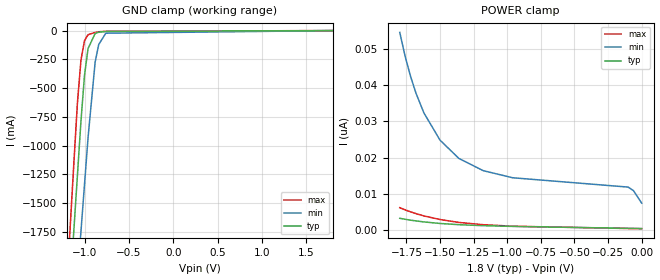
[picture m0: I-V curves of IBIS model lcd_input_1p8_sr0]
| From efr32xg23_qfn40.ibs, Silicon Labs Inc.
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|   Model lcd_input_1p8_sr0
[Model]  lcd_input_1p8_sr0
Model_type Input
C_comp   1.6300pF   1.4000pF   2.7000pF
[Temperature Range]   25.0000   0.1250k   -40.0000
[Pullup Reference]   1.8000V   1.6200V   1.9800V
[Pulldown Reference]   0.0V   0.0V   0.0V
[POWER Clamp Reference]   1.8000V   1.6200V   1.9800V
[GND Clamp Reference]   0.0V   0.0V   0.0V
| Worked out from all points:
|   GND clamp passes 1 mA (typ) near -0.56 V on its own axis
[GND_clamp]
|Voltage   I(typ)   I(min)   I(max)
-1.8V     -9.867A    -9.569A    -10.32A
-1.2V     -2.688A    -3.389A    -2.223A
-1.16V    -2.211A    -2.978A    -1.687A
-1.12V    -1.735A    -2.567A    -1.152A
-1.08V    -1.26A     -2.157A    -630.3mA
-1.04V    -786.2mA   -1.747A    -256.2mA
-1V       -388.1mA   -1.338A    -87.58mA
-960mV    -155.8mA   -930mA     -35.74mA
-880mV    -25.03mA   -272.7mA   -16.29mA
-840mV    -13.92mA   -121.5mA   -10.46mA
-760mV    -7.819mA   -22.78mA   -6.532mA
1.8V      420.7pA    11.94nA    334.2pA
[POWER_clamp]
|Voltage   I(typ)   I(min)   I(max)
-1.8V     3.264nA    54.56nA    6.193nA
-1.76V    2.994nA    47.98nA    5.591nA
-1.72V    2.754nA    42.48nA    5.047nA
-1.68V    2.541nA    37.87nA    4.559nA
-1.62V    2.263nA    32.33nA    3.919nA
-1.5V     1.838nA    24.81nA    2.92nA
-1.36V    1.501nA    19.78nA    2.122nA
-1.18V    1.228nA    16.42nA    1.492nA
-960mV    1.024nA    14.45nA    1.077nA
-100mV    499.2pA    11.87nA    445.7pA
-60mV     472.6pA    10.86nA    433.4pA
0V        420.7pA    7.448nA    403.8pA
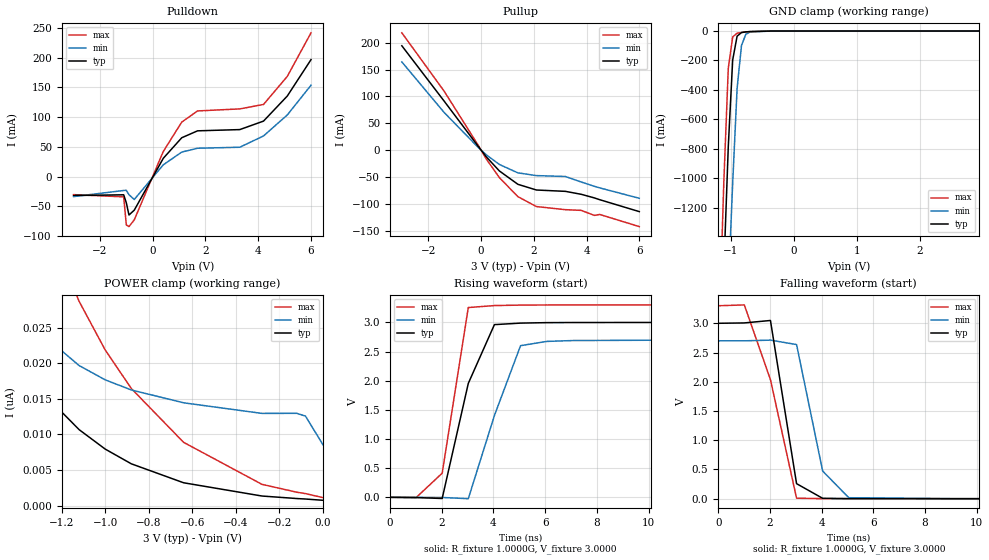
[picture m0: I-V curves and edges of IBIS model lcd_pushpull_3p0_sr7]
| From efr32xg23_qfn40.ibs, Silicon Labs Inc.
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|   Model lcd_pushpull_3p0_sr7
[Model]  lcd_pushpull_3p0_sr7
Model_type 3-state
Polarity   Non-Inverting
Enable   Active-High
C_comp   1.6300pF   1.4000pF   2.7000pF
[Temperature Range]   25.0000   0.1250k   -40.0000
[Pullup Reference]   3.0000V   2.7000V   3.3000V
[Pulldown Reference]   0.0V   0.0V   0.0V
[POWER Clamp Reference]   3.0000V   2.7000V   3.3000V
[GND Clamp Reference]   0.0V   0.0V   0.0V
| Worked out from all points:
|   slope of the pulldown table from 0 to 0.45 V, typ, clamps not added: 13.2 ohm
|   slope of the pullup table from 0 to 0.45 V, typ, clamps not added: 16.9 ohm
|   GND clamp passes 1 mA (typ) near -0.56 V on its own axis
|   rising waveform, R_fixture 1.0000G, V_fixture 3.0000: 20-80 % time 1.14ns typ, 1.25ns min, 704ps max; typ from 0 V to 3 V
|   falling waveform, R_fixture 1.0000G, V_fixture 3.0000: 20-80 % time 651ps typ, 756ps min, 1.16ns max; typ from 3 V to 0 V
[Pulldown]
|Voltage   I(typ)   I(min)   I(max)
-3V       -31.58mA   -33.4mA    -30.1mA
-1.1V     -30.4mA    -23.12mA   -33.84mA
-1V       -43.97mA   -22.88mA   -81.12mA
-900mV    -64.37mA   -30.22mA   -83.83mA
-700mV    -56.23mA   -38.35mA   -72.61mA
400mV     30.95mA    19.99mA    42.35mA
1.1V      65.5mA     41.43mA    91.79mA
1.7V      77.14mA    47.89mA    110.6mA
3.3V      79.23mA    49.55mA    114mA
4.2V      93.5mA     68.54mA    121.5mA
5.1V      135.6mA    103.8mA    168.6mA
6V        196.8mA    153.8mA    241.9mA
[Pullup]
|Voltage   I(typ)   I(min)   I(max)
-3V       194.2mA    164.1mA    218.3mA
-1.4V     91.4mA     70.21mA    109.9mA
-100mV    6.625mA    4.686mA    8.557mA
200mV     -12.59mA   -8.838mA   -16.56mA
700mV     -39mA      -26.89mA   -51.48mA
1.4V      -63.77mA   -42.47mA   -86.76mA
2.1V      -74.37mA   -47.55mA   -105.2mA
3.2V      -76.89mA   -49.24mA   -111mA
3.8V      -82.38mA   -59.49mA   -112.3mA
4.3V      -89.13mA   -67.54mA   -121.7mA
4.5V      -92.42mA   -70.43mA   -119.9mA
6V        -114.6mA   -89.81mA   -142.5mA
[GND_clamp]
|Voltage   I(typ)   I(min)   I(max)
-3V       -24.27A    -21.95A    -26.57A
-1.18V    -2.447A    -3.183A    -1.952A
-1.11V    -1.614A    -2.464A    -1.015A
-1.04V    -784mA     -1.746A    -252.8mA
-970mV    -196.2mA   -1.031A    -40.03mA
-900mV    -35mA      -390.7mA   -14.95mA
-830mV    -10.34mA   -96.94mA   -9.948mA
-760mV    -5.711mA   -21.43mA   -6.561mA
-690mV    -3.47mA    -6.05mA    -3.879mA
-340mV    -10.36uA   -45.49uA   -3.3uA
2.95V     657.9pA    12.89nA    538.5pA
[POWER_clamp]
|Voltage   I(typ)   I(min)   I(max)
-3V       338.2nA    9.289uA    586.7nA
-1.56V    29.18nA    39.44nA    70.52nA
-1.4V     20.57nA    28.74nA    51.74nA
-1.28V    15.63nA    23.83nA    40.5nA
-1.12V    10.68nA    19.68nA    28.7nA
-1V       7.945nA    17.67nA    21.86nA
-880mV    5.879nA    16.25nA    16.45nA
-640mV    3.219nA    14.45nA    8.897nA
-280mV    1.357nA    12.96nA    2.997nA
-120mV    1.003nA    12.97nA    1.894nA
-80mV     936.4pA    12.58nA    1.698nA
0V        757.3pA    8.576nA    1.134nA
[Ramp]
| variable   typ   min   max
dV/dt_r  1.7971/1.1476n   1.6163/1.2582n   1.9775/0.7045n
dV/dt_f  1.7980/0.6538n   1.6172/0.7624n   1.9783/1.1625n
R_load = 10.0000k
[Rising Waveform]
R_fixture= 1.0000G
V_fixture= 3.0000
V_fixture_min= 2.7000
V_fixture_max= 3.3000
|time   V(typ)   V(min)   V(max)
0s        2.714uV    4.972uV    1.54uV
1.01ns    -4.146mV   -950.5uV   -5.115mV
2.02ns    -20.05mV   -2.606mV   413.9mV
3.03ns    1.954V     -23.67mV   3.255V
4.04ns    2.962V     1.403V     3.289V
5.051ns   2.988V     2.601V     3.297V
6.061ns   2.996V     2.674V     3.299V
7.071ns   2.998V     2.689V     3.3V
13.13ns   3V         2.7V       3.3V
100ns     3V         2.7V       3.3V
[Falling Waveform]
R_fixture= 1.0000G
V_fixture= 3.0000
V_fixture_min= 2.7000
V_fixture_max= 3.3000
|time   V(typ)   V(min)   V(max)
0s        3V         2.7V       3.3V
1.01ns    3.006V     2.7V       3.314V
2.02ns    3.048V     2.712V     2.036V
3.03ns    257.3mV    2.636V     8.468mV
4.04ns    6.292mV    472.4mV    1.168mV
5.051ns   1.448mV    16.61mV    289.8uV
9.091ns   66.73uV    434.1uV    24.35uV
100ns     2.693uV    6.052uV    1.56uV
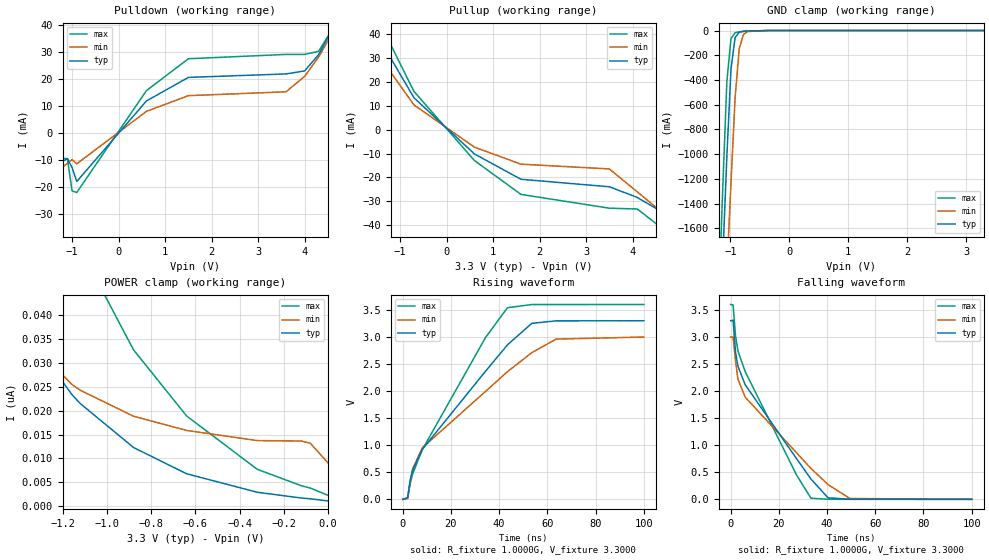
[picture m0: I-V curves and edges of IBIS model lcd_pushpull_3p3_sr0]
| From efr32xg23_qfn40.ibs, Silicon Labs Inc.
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|   Model lcd_pushpull_3p3_sr0
[Model]  lcd_pushpull_3p3_sr0
Model_type 3-state
Polarity   Non-Inverting
Enable   Active-High
C_comp   1.6300pF   1.4000pF   2.7000pF
[Temperature Range]   25.0000   0.1250k   -40.0000
[Pullup Reference]   3.3000V   3.0000V   3.6000V
[Pulldown Reference]   0.0V   0.0V   0.0V
[POWER Clamp Reference]   3.3000V   3.0000V   3.6000V
[GND Clamp Reference]   0.0V   0.0V   0.0V
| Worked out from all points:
|   slope of the pulldown table from 0 to 0.495 V, typ, clamps not added: 48.7 ohm
|   slope of the pullup table from 0 to 0.495 V, typ, clamps not added: 57.6 ohm
|   GND clamp passes 1 mA (typ) near -0.56 V on its own axis
|   rising waveform, R_fixture 1.0000G, V_fixture 3.3000: 20-80 % time 34.1ns typ, 40.2ns min, 26.8ns max; typ from 0 V to 3.3 V
|   falling waveform, R_fixture 1.0000G, V_fixture 3.3000: 20-80 % time 26.4ns typ, 30.2ns min, 21.8ns max; typ from 3.3 V to 0 V
[Pulldown]
|Voltage   I(typ)   I(min)   I(max)
-3.3V     -32.48mA   -36.78mA   -26.72mA
-1.2V     -10.41mA   -12.59mA   -9.355mA
-1.1V     -9.492mA   -11.16mA   -9.469mA
-1V       -12.79mA   -9.82mA    -21.42mA
-900mV    -17.92mA   -11.39mA   -21.97mA
600mV     11.83mA    7.984mA    15.65mA
1.5V      20.51mA    13.77mA    27.39mA
3.6V      21.79mA    15.2mA     28.99mA
4V        22.91mA    20.9mA     29mA
4.3V      28.91mA    28.04mA    30.13mA
4.7V      41.74mA    40.01mA    41.16mA
6.6V      135.1mA    124.4mA    142.2mA
[Pullup]
|Voltage   I(typ)   I(min)   I(max)
-3.3V     128.6mA    110.9mA    144.8mA
-1.9V     57.64mA    47.01mA    67.7mA
-1.7V     48.63mA    39.45mA    57.37mA
-1.5V     40.07mA    32.37mA    47.44mA
-700mV    13.41mA    10.43mA    16.1mA
600mV     -10.16mA   -7.306mA   -12.92mA
1.6V      -20.79mA   -14.45mA   -27.14mA
3.5V      -23.94mA   -16.45mA   -32.93mA
4.1V      -28.41mA   -26.06mA   -33.27mA
4.6V      -34.14mA   -34.13mA   -40.85mA
5.6V      -47.68mA   -46.64mA   -48.47mA
6.6V      -57.76mA   -56.29mA   -58.41mA
[GND_clamp]
|Voltage   I(typ)   I(min)   I(max)
-3.3V     -27.87A    -25.05A    -30.64A
-1.2V     -2.686A    -3.389A    -2.22A
-1.13V    -1.852A    -2.669A    -1.282A
-1.06V    -1.021A    -1.951A    -413.8mA
-990mV    -311.8mA   -1.235A    -64.72mA
-920mV    -56.25mA   -542.5mA   -17.8mA
-850mV    -13.45mA   -148.5mA   -11.08mA
-780mV    -6.591mA   -32.68mA   -7.457mA
-710mV    -4.029mA   -8.323mA   -4.574mA
-360mV    -18.91uA   -70.05uA   -6.844uA
3.3V      1.07nA     13.64nA    781.9pA
[POWER_clamp]
|Voltage   I(typ)   I(min)   I(max)
-3.28V    727.8nA    32.99uA    1.086uA
-1.6V     57.64nA    55.61nA    128.6nA
-1.56V    53.42nA    50.92nA    120.3nA
-1.4V     38.98nA    37.13nA    91.2nA
-1.16V    23.46nA    25.56nA    58.31nA
-1.12V    21.47nA    24.28nA    53.91nA
-880mV    12.29nA    18.85nA    32.79nA
-640mV    6.783nA    15.87nA    18.92nA
-320mV    2.894nA    13.73nA    7.713nA
-120mV    1.684nA    13.64nA    4.257nA
-80mV     1.52nA     13.19nA    3.779nA
0V        1.07nA     9.091nA    2.25nA
[Ramp]
| variable   typ   min   max
dV/dt_r  1.9617/37.0242n   1.7688/45.3295n   2.1477/28.3047n
dV/dt_f  1.9693/29.4329n   1.7815/35.6043n   2.1526/23.4418n
R_load = 10.0000k
[Rising Waveform]
R_fixture= 1.0000G
V_fixture= 3.3000
V_fixture_min= 3.0000
V_fixture_max= 3.6000
|time   V(typ)   V(min)   V(max)
0s        212.3uV    401.5uV    127.4uV
2.02ns    29.92mV    25.4mV     16.45mV
3.03ns    337.6mV    310.8mV    279.7mV
4.04ns    529.4mV    558.1mV    461.4mV
8.081ns   920.7mV    951.4mV    915mV
34.34ns   2.367V     1.994V     2.989V
43.43ns   2.853V     2.358V     3.54V
53.54ns   3.252V     2.71V      3.599V
63.64ns   3.298V     2.961V     3.599V
100ns     3.3V       2.999V     3.6V
[Falling Waveform]
R_fixture= 1.0000G
V_fixture= 3.3000
V_fixture_min= 3.0000
V_fixture_max= 3.6000
|time   V(typ)   V(min)   V(max)
0s        3.3V       2.999V     3.6V
1.01ns    3.31V      2.997V     3.591V
2.02ns    2.719V     2.559V     3.02V
3.03ns    2.457V     2.218V     2.739V
6.061ns   2.115V     1.887V     2.358V
27.27ns   755.7mV    863.5mV    454.2mV
33.33ns   374.4mV    570.6mV    20.5mV
40.4ns    28mV       272.1mV    959.5uV
49.49ns   1.325mV    15.29mV    469.3uV
100ns     214.5uV    417uV      127.9uV
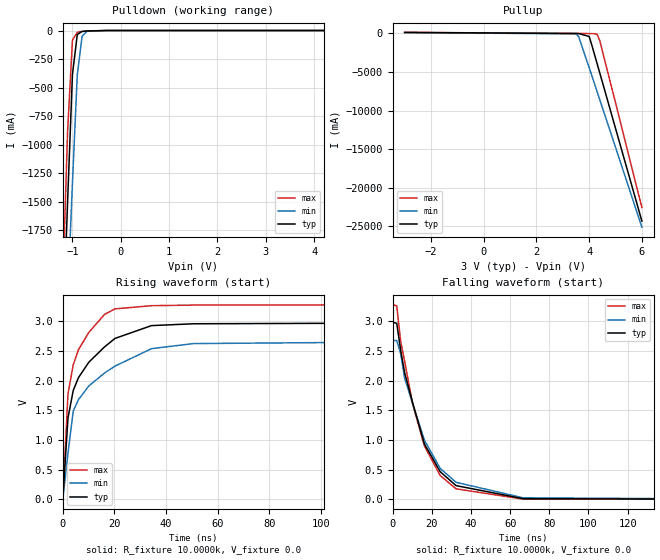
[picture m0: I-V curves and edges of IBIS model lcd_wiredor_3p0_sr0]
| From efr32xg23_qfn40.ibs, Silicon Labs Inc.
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|   Model lcd_wiredor_3p0_sr0
[Model]  lcd_wiredor_3p0_sr0
Model_type Output
Polarity   Non-Inverting
Enable   Active-Low
C_comp   1.6300pF   1.4000pF   2.7000pF
[Temperature Range]   25.0000   0.1250k   -40.0000
[Pullup Reference]   3.0000V   2.7000V   3.3000V
[Pulldown Reference]   0.0V   0.0V   0.0V
[POWER Clamp Reference]   3.0000V   2.7000V   3.3000V
[GND Clamp Reference]   0.0V   0.0V   0.0V
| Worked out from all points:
|   slope of the pullup table from 0 to 0.45 V, typ, clamps not added: 61.2 ohm
|   rising waveform, R_fixture 10.0000k, V_fixture 0.0: 20-80 % time 10.8ns typ, 15.2ns min, 6.61ns max; typ from 0 V to 2.98 V
|   falling waveform, R_fixture 10.0000k, V_fixture 0.0: 20-80 % time 16.7ns typ, 18.3ns min, 15.1ns max; typ from 2.98 V to 0 V
[Pulldown]
|Voltage   I(typ)   I(min)   I(max)
-3V       -24.27A    -21.95A    -26.57A
-1.2V     -2.686A    -3.389A    -2.22A
-1.1V     -1.495A    -2.361A    -881.8mA
-1V       -385.8mA   -1.337A    -84.19mA
-900mV    -34.99mA   -390.7mA   -14.95mA
-800mV    -7.703mA   -50.4mA    -8.403mA
-700mV    -3.742mA   -7.062mA   -4.219mA
-300mV    -2.847uA   -17.98uA   -692.6nA
6V        338.2nA    35.99uA    408.8nA
[Pullup]
|Voltage   I(typ)   I(min)   I(max)
-3V       110.5mA    92.38mA    126.9mA
3.5V      -20.93mA   -70.49mA   -28.69mA
3.6V      -22.98mA   -412.2mA   -28.7mA
4V        -413.4mA   -4.443A    -35.96mA
4.1V      -1.522A    -5.474A    -42.03mA
4.2V      -2.714A    -6.505A    -50.3mA
4.3V      -3.912A    -7.537A    -120.8mA
4.4V      -5.109A    -8.569A    -915.3mA
4.5V      -6.307A    -9.602A    -2.255A
4.7V      -8.705A    -11.67A    -4.954A
4.8V      -9.905A    -12.7A     -6.304A
6V        -24.32A    -25.1A     -22.56A
[Ramp]
| variable   typ   min   max
dV/dt_r  1.7893/10.7796n   1.6058/15.1523n   1.9711/6.6087n
dV/dt_f  49.0481u/0.2795n   58.2800u/3.7685p   62.0810u/1.8445p
R_load = 10.0000k
[Rising Waveform]
R_fixture= 10.0000k
V_fixture= 0.0
V_fixture_min= 0.0
V_fixture_max= 0.0
|time   V(typ)   V(min)   V(max)
0s        4.624uV    47.91uV    4.748uV
2.02ns    1.373V     775.7mV    1.78V
4.04ns    1.834V     1.488V     2.267V
6.061ns   2.051V     1.681V     2.523V
10.1ns    2.313V     1.912V     2.816V
16.16ns   2.57V      2.13V      3.118V
20.2ns    2.713V     2.246V     3.211V
34.34ns   2.929V     2.54V      3.265V
50.51ns   2.96V      2.626V     3.275V
200ns     2.982V     2.676V     3.285V
[Falling Waveform]
R_fixture= 10.0000k
V_fixture= 0.0
V_fixture_min= 0.0
V_fixture_max= 0.0
|time   V(typ)   V(min)   V(max)
0s        2.984V     2.679V     3.286V
2.02ns    2.97V      2.679V     3.263V
4.04ns    2.511V     2.457V     2.66V
6.061ns   2.135V     2.042V     2.329V
10.1ns    1.634V     1.618V     1.613V
16.16ns   933.7mV    998.1mV    898.7mV
24.24ns   464.9mV    520.4mV    400.8mV
32.32ns   230.9mV    286.6mV    176.8mV
66.67ns   10mV       24.73mV    2.331mV
200ns     -452.1uV   290.5uV    -558.3uV
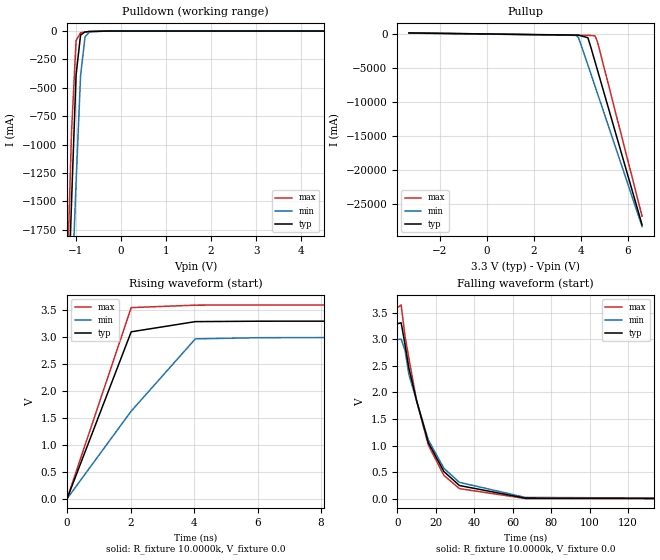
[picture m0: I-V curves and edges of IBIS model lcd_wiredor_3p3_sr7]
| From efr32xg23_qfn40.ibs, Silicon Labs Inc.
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|   Model lcd_wiredor_3p3_sr7
[Model]  lcd_wiredor_3p3_sr7
Model_type Output
Polarity   Non-Inverting
Enable   Active-Low
C_comp   1.6300pF   1.4000pF   2.7000pF
[Temperature Range]   25.0000   0.1250k   -40.0000
[Pullup Reference]   3.3000V   3.0000V   3.6000V
[Pulldown Reference]   0.0V   0.0V   0.0V
[POWER Clamp Reference]   3.3000V   3.0000V   3.6000V
[GND Clamp Reference]   0.0V   0.0V   0.0V
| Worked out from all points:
|   slope of the pullup table from 0 to 0.495 V, typ, clamps not added: 15.9 ohm
|   rising waveform, R_fixture 10.0000k, V_fixture 0.0: 20-80 % time 1.29ns typ, 2.44ns min, 1.23ns max; typ from 0 V to 3.29 V
|   falling waveform, R_fixture 10.0000k, V_fixture 0.0: 20-80 % time 16.2ns typ, 17.9ns min, 14.6ns max; typ from 3.29 V to 0 V
[Pulldown]
|Voltage   I(typ)   I(min)   I(max)
-3.3V     -27.87A    -25.05A    -30.64A
-1.2V     -2.686A    -3.389A    -2.22A
-1.1V     -1.495A    -2.361A    -881.8mA
-1V       -385.8mA   -1.337A    -84.19mA
-900mV    -35mA      -390.8mA   -14.95mA
-800mV    -7.709mA   -50.4mA    -8.405mA
-700mV    -3.744mA   -7.067mA   -4.22mA
-300mV    -2.853uA   -17.99uA   -699.1nA
6.6V      752.9nA    140.4uA    817.4nA
[Pullup]
|Voltage   I(typ)   I(min)   I(max)
-3.3V     221.2mA    195.6mA    241.7mA
3.8V      -92.93mA   -118.6mA   -128.7mA
3.9V      -95.18mA   -460.7mA   -128.9mA
4.3V      -487mA     -4.492A    -137mA
4.4V      -1.596A    -5.524A    -143.5mA
4.5V      -2.788A    -6.555A    -152.2mA
4.6V      -3.984A    -7.588A    -223.2mA
4.7V      -5.183A    -8.62A     -1.018A
4.8V      -6.381A    -9.652A    -2.357A
5V        -8.78A     -11.72A    -5.054A
5.1V      -9.98A     -12.75A    -6.408A
6.6V      -28.01A    -28.26A    -26.74A
[Ramp]
| variable   typ   min   max
dV/dt_r  1.9770/1.2898n   1.7962/2.4360n   2.1574/1.2292n
dV/dt_f  0.1325m/4.5745p   76.2395u/4.8026p   0.2279m/6.0981p
R_load = 10.0000k
[Rising Waveform]
R_fixture= 10.0000k
V_fixture= 0.0
V_fixture_min= 0.0
V_fixture_max= 0.0
|time   V(typ)   V(min)   V(max)
0s        5.069uV    44.89uV    5.493uV
2.02ns    3.097V     1.625V     3.546V
4.04ns    3.286V     2.966V     3.592V
6.061ns   3.294V     2.988V     3.595V
12.12ns   3.295V     2.994V     3.596V
200ns     3.295V     2.994V     3.596V
[Falling Waveform]
R_fixture= 10.0000k
V_fixture= 0.0
V_fixture_min= 0.0
V_fixture_max= 0.0
|time   V(typ)   V(min)   V(max)
0s        3.295V     2.994V     3.596V
2.02ns    3.312V     3.006V     3.649V
4.04ns    2.9V       2.792V     3.056V
6.061ns   2.454V     2.336V     2.64V
10.1ns    1.841V     1.834V     1.834V
16.16ns   1.054V     1.104V     1.008V
24.24ns   511.9mV    571.8mV    439.2mV
32.32ns   247.5mV    306.7mV    189.3mV
66.67ns   9.079mV    23.44mV    2.104mV
200ns     -487.8uV   160.8uV    -555.1uV
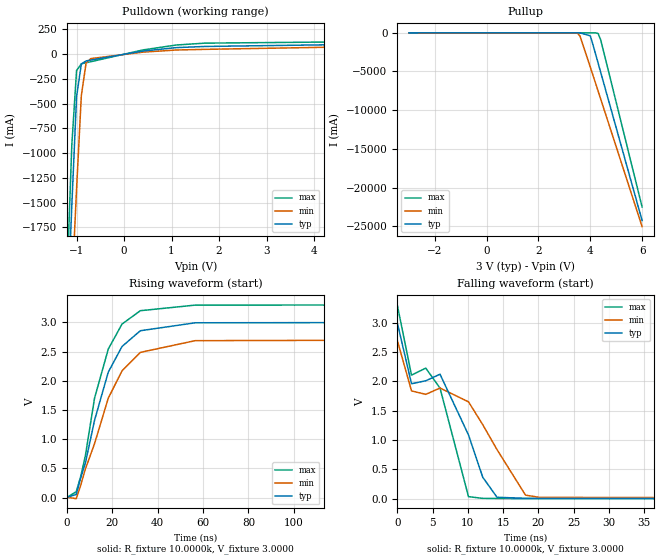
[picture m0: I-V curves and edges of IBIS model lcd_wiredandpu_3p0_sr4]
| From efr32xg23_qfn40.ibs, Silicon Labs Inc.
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|   Model lcd_wiredandpu_3p0_sr4
[Model]  lcd_wiredandpu_3p0_sr4
Model_type Output
Polarity   Inverting
Enable   Active-Low
C_comp   1.6300pF   1.4000pF   2.7000pF
[Temperature Range]   25.0000   0.1250k   -40.0000
[Pullup Reference]   3.0000V   2.7000V   3.3000V
[Pulldown Reference]   0.0V   0.0V   0.0V
[POWER Clamp Reference]   3.0000V   2.7000V   3.3000V
[GND Clamp Reference]   0.0V   0.0V   0.0V
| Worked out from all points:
|   slope of the pulldown table from 0 to 0.45 V, typ, clamps not added: 13.2 ohm
|   slope of the pullup table from 0 to 0.45 V, typ, clamps not added: 40.2 kohm
|   rising waveform, R_fixture 10.0000k, V_fixture 3.0000: 20-80 % time 13.1ns typ, 15.5ns min, 11.5ns max; typ from 0.003 V to 3 V
|   falling waveform, R_fixture 10.0000k, V_fixture 3.0000: 20-80 % time 10.3ns typ, 14.1ns min, 7.54ns max; typ from 3 V to 0.003 V
[Pulldown]
|Voltage   I(typ)   I(min)   I(max)
-3V       -24.3A     -21.99A    -26.6A
-1.2V     -2.716A    -3.412A    -2.254A
-1.1V     -1.526A    -2.385A    -915.6mA
-1V       -429.7mA   -1.36A     -165.3mA
-900mV    -99.37mA   -421mA     -98.78mA
-800mV    -69.26mA   -90.62mA   -87.32mA
-700mV    -59.97mA   -45.41mA   -76.82mA
400mV     30.95mA    19.99mA    42.35mA
1.1V      65.5mA     41.43mA    91.79mA
1.7V      77.14mA    47.89mA    110.6mA
4.2V      93.51mA    68.56mA    121.5mA
6V        196.9mA    153.8mA    241.9mA
[Pullup]
|Voltage   I(typ)   I(min)   I(max)
-3V       74.15uA    73.25uA    86.28uA
3.5V      -515.4uA   -50.46mA   -100.7uA
3.6V      -1.645mA   -390.8mA   -104.2uA
4V        -385.9mA   -4.417A    -4.327mA
4.1V      -1.495A    -5.447A    -8.512mA
4.2V      -2.686A    -6.476A    -15.06mA
4.3V      -3.882A    -7.507A    -84.3mA
4.4V      -5.077A    -8.538A    -881.9mA
4.5V      -6.274A    -9.569A    -2.22A
4.7V      -8.669A    -11.63A    -4.917A
4.8V      -9.868A    -12.66A    -6.266A
6V        -24.27A    -25.05A    -22.51A
[Ramp]
| variable   typ   min   max
dV/dt_r  0.3580/12.8648n   0.2880/14.3502n   0.4423/11.6048n
dV/dt_f  1.7980/10.2986n   1.6171/14.1264n   1.9783/7.5424n
R_load = 10.0000k
[Rising Waveform]
R_fixture= 10.0000k
V_fixture= 3.0000
V_fixture_min= 2.7000
V_fixture_max= 3.3000
|time   V(typ)   V(min)   V(max)
0s        3.394mV    4.689mV    2.757mV
4.04ns    53.19mV    -20.17mV   100.1mV
6.061ns   341.8mV    215.5mV    367.1mV
8.081ns   590.9mV    488.8mV    718.2mV
12.12ns   1.323V     923.2mV    1.703V
18.18ns   2.149V     1.702V     2.544V
24.24ns   2.588V     2.171V     2.972V
32.32ns   2.858V     2.487V     3.201V
56.57ns   2.994V     2.688V     3.297V
200ns     3V         2.7V       3.3V
[Falling Waveform]
R_fixture= 10.0000k
V_fixture= 3.0000
V_fixture_min= 2.7000
V_fixture_max= 3.3000
|time   V(typ)   V(min)   V(max)
0s        3V         2.7V       3.3V
2.02ns    1.959V     1.837V     2.105V
4.04ns    2.009V     1.778V     2.225V
6.061ns   2.121V     1.886V     1.885V
10.1ns    1.087V     1.651V     37.25mV
12.12ns   367.6mV    1.262V     8.566mV
14.14ns   27.15mV    838.5mV    6.037mV
18.18ns   8.527mV    63.5mV     4.632mV
20.2ns    7.097mV    24.75mV    4.344mV
200ns     3.395mV    4.693mV    2.758mV
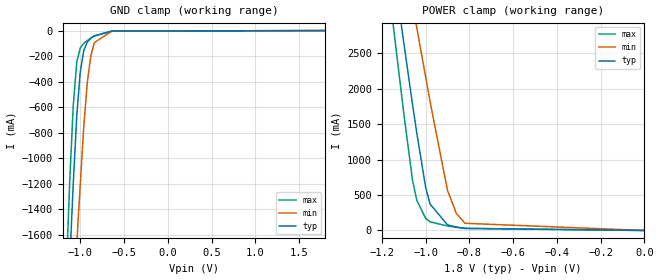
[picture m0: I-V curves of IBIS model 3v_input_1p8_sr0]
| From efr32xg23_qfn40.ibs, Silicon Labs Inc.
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|   Model 3v_input_1p8_sr0
[Model]  3v_input_1p8_sr0
Model_type Input
C_comp   1.6300pF   1.4000pF   2.7000pF
[Temperature Range]   25.0000   0.1250k   -40.0000
[Pullup Reference]   1.8000V   1.6200V   1.9800V
[Pulldown Reference]   0.0V   0.0V   0.0V
[POWER Clamp Reference]   1.8000V   1.6200V   1.9800V
[GND Clamp Reference]   0.0V   0.0V   0.0V
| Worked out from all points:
|   GND clamp passes 1 mA (typ) near -0.52 V on its own axis
|   POWER clamp passes 1 mA (typ) near -0.53 V on its own axis
[GND_clamp]
|Voltage   I(typ)   I(min)   I(max)
-1.8V     -14.24A    -14.11A    -14.46A
-1.16V    -2.476A    -3.328A    -1.893A
-1.12V    -1.809A    -2.723A    -1.176A
-1.08V    -1.199A    -2.174A    -584.5mA
-1.04V    -665.3mA   -1.671A    -246.2mA
-1V       -325.1mA   -1.206A    -136.4mA
-960mV    -156.4mA   -753.1mA   -99.65mA
-920mV    -90.21mA   -408.8mA   -78.05mA
-880mV    -60.4mA    -199.9mA   -59.73mA
-840mV    -41.37mA   -94.67mA   -43.12mA
-640mV    -3.804mA   -4.268mA   -4.1mA
1.8V      625.9pA    920.5nA    498.3pA
[POWER_clamp]
|Voltage   I(typ)   I(min)   I(max)
-1.8V     20.85A     19.71A     22.07A
-1.16V    4.023A     5.096A     3.217A
-1.14V    3.56A      4.702A     2.691A
-1.1V     2.657A     3.938A     1.662A
-1.06V    1.784A     3.203A     710.9mA
-1.04V    1.371A     2.858A     424.9mA
-1V       612.3mA    2.171A     172.3mA
-980mV    375.2mA    1.828A     122.5mA
-900mV    79.36mA    567.5mA    63.7mA
-860mV    47.61mA    243.6mA    45.04mA
-820mV    29.31mA    101.4mA    29.65mA
0V        625.9pA    9.472nA    580.1pA
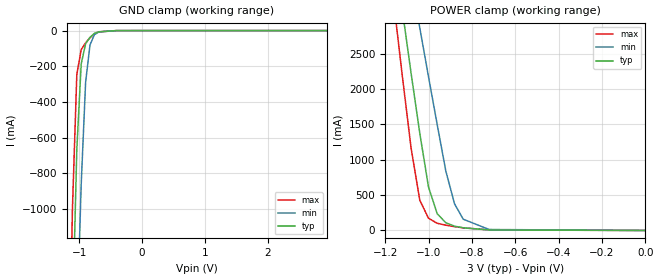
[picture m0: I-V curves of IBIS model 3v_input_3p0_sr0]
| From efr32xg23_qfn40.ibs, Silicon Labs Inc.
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|   Model 3v_input_3p0_sr0
[Model]  3v_input_3p0_sr0
Model_type Input
C_comp   1.6300pF   1.4000pF   2.7000pF
[Temperature Range]   25.0000   0.1250k   -40.0000
[Pullup Reference]   3.0000V   2.7000V   3.3000V
[Pulldown Reference]   0.0V   0.0V   0.0V
[POWER Clamp Reference]   3.0000V   2.7000V   3.3000V
[GND Clamp Reference]   0.0V   0.0V   0.0V
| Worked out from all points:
|   GND clamp passes 1 mA (typ) near -0.52 V on its own axis
|   POWER clamp passes 1 mA (typ) near -0.53 V on its own axis
[GND_clamp]
|Voltage   I(typ)   I(min)   I(max)
-3V       -32.58A    -30.59A    -34.3A
-1.18V    -2.82A     -3.643A    -2.261A
-1.11V    -1.644A    -2.575A    -1.001A
-1.04V    -666.4mA   -1.673A    -246.5mA
-970mV    -186.7mA   -861.8mA   -106.7mA
-900mV    -73.86mA   -290.7mA   -68.98mA
-830mV    -38.01mA   -80.48mA   -39.62mA
-760mV    -15.97mA   -23.02mA   -17.36mA
-690mV    -6.612mA   -7.853mA   -7.292mA
-410mV    -117.4uA   -298.1uA   -56.99uA
2.95V     978pA      6.282uA    846.4pA
[POWER_clamp]
|Voltage   I(typ)   I(min)   I(max)
-3V       48.87A     43.6A      53.88A
-1.16V    4.025A     5.101A     3.218A
-1.12V    3.102A     4.315A     2.168A
-1.08V    2.218A     3.569A     1.158A
-1.04V    1.372A     2.862A     425.9mA
-1V       614.1mA    2.175A     173.1mA
-960mV    237.5mA    1.499A     101.5mA
-920mV    109mA      838.4mA    74.91mA
-880mV    61.26mA    377.1mA    54.02mA
-840mV    37.84mA    159.1mA    37.05mA
-720mV    7.412mA    13.58mA    7.87mA
0V        1.019nA    10.64nA    1.026nA
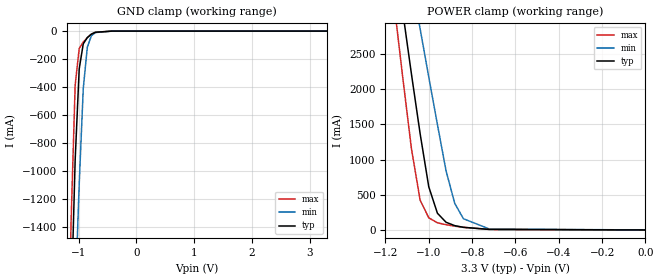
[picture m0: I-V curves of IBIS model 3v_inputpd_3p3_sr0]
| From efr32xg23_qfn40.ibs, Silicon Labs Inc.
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|   Model 3v_inputpd_3p3_sr0
[Model]  3v_inputpd_3p3_sr0
Model_type Input
C_comp   1.6300pF   1.4000pF   2.7000pF
[Temperature Range]   25.0000   0.1250k   -40.0000
[Pullup Reference]   3.3000V   3.0000V   3.6000V
[Pulldown Reference]   0.0V   0.0V   0.0V
[POWER Clamp Reference]   3.3000V   3.0000V   3.6000V
[GND Clamp Reference]   0.0V   0.0V   0.0V
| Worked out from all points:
|   GND clamp passes 1 mA (typ) near -0.52 V on its own axis
|   POWER clamp passes 1 mA (typ) near -0.52 V on its own axis
[GND_clamp]
|Voltage   I(typ)   I(min)   I(max)
-3.3V     -36.82A    -34.37A    -38.92A
-1.2V     -3.169A    -3.961A    -2.635A
-1.13V    -1.976A    -2.875A    -1.354A
-1.06V    -919.5mA   -1.925A    -386.3mA
-990mV    -269.8mA   -1.092A    -124.3mA
-920mV    -91.08mA   -411.1mA   -78.23mA
-850mV    -46.31mA   -116.2mA   -47.39mA
-780mV    -21.48mA   -33.47mA   -23.01mA
-710mV    -8.346mA   -10.37mA   -9.205mA
-430mV    -196.9uA   -429.1uA   -112.3uA
3.3V      74.76uA    87.41uA    86.61uA
[POWER_clamp]
|Voltage   I(typ)   I(min)   I(max)
-3.28V    55.25A     49.02A     61.14A
-1.16V    4.026A     5.102A     3.218A
-1.12V    3.102A     4.316A     2.168A
-1.08V    2.219A     3.57A      1.158A
-1.04V    1.373A     2.863A     426.1mA
-1V       614.5mA    2.175A     173.3mA
-960mV    237.8mA    1.5A       101.6mA
-920mV    109.3mA    839mA      75.07mA
-880mV    61.49mA    377.8mA    54.18mA
-840mV    38.03mA    159.6mA    37.2mA
-720mV    7.541mA    13.82mA    7.997mA
0V        74.76uA    59.13uA    94.48uA
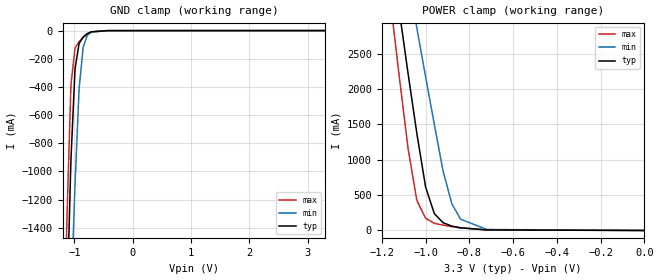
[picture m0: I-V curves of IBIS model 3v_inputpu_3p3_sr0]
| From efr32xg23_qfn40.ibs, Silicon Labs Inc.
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|   Model 3v_inputpu_3p3_sr0
[Model]  3v_inputpu_3p3_sr0
Model_type Input
C_comp   1.6300pF   1.4000pF   2.7000pF
[Temperature Range]   25.0000   0.1250k   -40.0000
[Pullup Reference]   3.3000V   3.0000V   3.6000V
[Pulldown Reference]   0.0V   0.0V   0.0V
[POWER Clamp Reference]   3.3000V   3.0000V   3.6000V
[GND Clamp Reference]   0.0V   0.0V   0.0V
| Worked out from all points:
|   GND clamp passes 1 mA (typ) near -0.51 V on its own axis
|   POWER clamp passes 1 mA (typ) near -0.53 V on its own axis
[GND_clamp]
|Voltage   I(typ)   I(min)   I(max)
-3.3V     -36.82A    -34.37A    -38.92A
-1.2V     -3.17A     -3.961A    -2.635A
-1.13V    -1.976A    -2.876A    -1.355A
-1.06V    -919.5mA   -1.925A    -386.4mA
-990mV    -269.9mA   -1.092A    -124.4mA
-920mV    -91.16mA   -411.2mA   -78.32mA
-850mV    -46.38mA   -116.3mA   -47.49mA
-780mV    -21.56mA   -33.53mA   -23.11mA
-710mV    -8.42mA    -10.43mA   -9.299mA
-430mV    -271.4uA   -488.1uA   -206.4uA
3.3V      1.119nA    28.31uA    -7.841uA
[POWER_clamp]
|Voltage   I(typ)   I(min)   I(max)
-3.28V    55.25A     49.02A     61.14A
-1.16V    4.026A     5.102A     3.218A
-1.12V    3.102A     4.316A     2.168A
-1.08V    2.218A     3.57A      1.158A
-1.04V    1.373A     2.863A     426mA
-1V       614.5mA    2.175A     173.2mA
-960mV    237.8mA    1.5A       101.5mA
-920mV    109.3mA    839mA      74.97mA
-880mV    61.41mA    377.7mA    54.08mA
-840mV    37.95mA    159.6mA    37.11mA
-720mV    7.466mA    13.76mA    7.903mA
0V        1.119nA    10.87nA    1.188nA
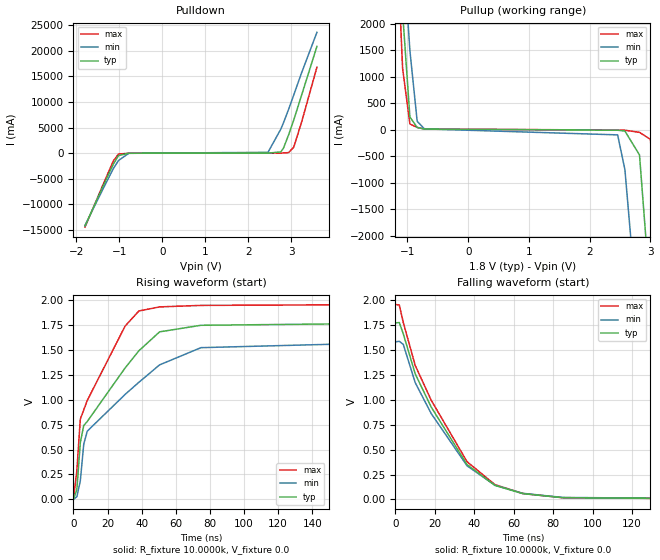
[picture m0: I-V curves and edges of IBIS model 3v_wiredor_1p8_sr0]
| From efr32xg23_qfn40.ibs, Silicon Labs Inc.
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|   Model 3v_wiredor_1p8_sr0
[Model]  3v_wiredor_1p8_sr0
Model_type Output
Polarity   Non-Inverting
Enable   Active-Low
C_comp   1.6300pF   1.4000pF   2.7000pF
[Temperature Range]   25.0000   0.1250k   -40.0000
[Pullup Reference]   1.8000V   1.6200V   1.9800V
[Pulldown Reference]   0.0V   0.0V   0.0V
[POWER Clamp Reference]   1.8000V   1.6200V   1.9800V
[GND Clamp Reference]   0.0V   0.0V   0.0V
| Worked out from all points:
|   slope of the pullup table from 0 to 0.27 V, typ, clamps not added: 170 ohm
|   rising waveform, R_fixture 10.0000k, V_fixture 0.0: 20-80 % time 31.7ns typ, 39.6ns min, 22.2ns max; typ from 0 V to 1.77 V
|   falling waveform, R_fixture 10.0000k, V_fixture 0.0: 20-80 % time 28.6ns typ, 29ns min, 29.1ns max; typ from 1.77 V to 0.001 V
[Pulldown]
|Voltage   I(typ)   I(min)   I(max)
-1.8V     -14.24A    -14.11A    -14.46A
-1.38V    -6.468A    -6.98A     -6.16A
-1.14V    -2.14A     -3.023A    -1.532A
-1.02V    -472.4mA   -1.439A    -175.3mA
-780mV    -21.13mA   -32.28mA   -22.88mA
2.46V     4.005mA    156.9mA    238.6uA
2.76V     235.8mA    4.702A     17.81mA
2.82V     958.6mA    5.911A     36.63mA
2.94V     3.56A      8.545A     100.8mA
3.06V     6.47A      11.36A     1.157A
3.24V     11.25A     15.63A     5.98A
3.6V      20.85A     23.6A      16.79A
[Pullup]
|Voltage   I(typ)   I(min)   I(max)
-1.8V     20.85A     19.71A     22.07A
-1.2V     4.979A     5.912A     4.301A
-1.08V    2.219A     3.567A     1.162A
-960mV    241.1mA    1.498A     109mA
-840mV    42.87mA    159.9mA    44.3mA
-720mV    12.28mA    16.09mA    14.65mA
2.46V     -8.699mA   -97.07mA   -6.739mA
2.58V     -25.15mA   -755.5mA   -8.985mA
2.82V     -476.4mA   -3.961A    -49.54mA
3V        -3.172A    -6.982A    -181.7mA
3.24V     -7.608A    -11.14A    -3.788A
3.6V      -14.25A    -16.86A    -11A
[Ramp]
| variable   typ   min   max
dV/dt_r  1.0634/31.6836n   0.9488/39.5880n   1.1753/22.2341n
dV/dt_f  2.4184u/14.3634n   53.2357u/30.9987n   4.5369u/2.3296p
R_load = 10.0000k
[Rising Waveform]
R_fixture= 10.0000k
V_fixture= 0.0
V_fixture_min= 0.0
V_fixture_max= 0.0
|time   V(typ)   V(min)   V(max)
0s        5.684uV    72.78uV    5.763uV
2.02ns    95.97mV    26.29mV    287.2mV
4.04ns    568.1mV    184.1mV    805.6mV
6.061ns   742mV      553.9mV    898.7mV
8.081ns   782.1mV    684.6mV    992.7mV
30.3ns    1.321V     1.055V     1.742V
38.38ns   1.494V     1.177V     1.894V
50.51ns   1.684V     1.352V     1.935V
74.75ns   1.75V      1.525V     1.95V
200ns     1.772V     1.581V     1.959V
[Falling Waveform]
R_fixture= 10.0000k
V_fixture= 0.0
V_fixture_min= 0.0
V_fixture_max= 0.0
|time   V(typ)   V(min)   V(max)
0s        1.773V     1.584V     1.959V
2.02ns    1.778V     1.589V     1.954V
4.04ns    1.664V     1.558V     1.778V
10.1ns    1.261V     1.173V     1.346V
18.18ns   928.7mV    863.5mV    997.5mV
36.36ns   349.7mV    337.7mV    378.9mV
50.51ns   140.8mV    142mV      148.5mV
64.65ns   57.81mV    61.04mV    59.18mV
84.85ns   17.38mV    19.7mV     16.91mV
200ns     956.4uV    1.285mV    776.6uV
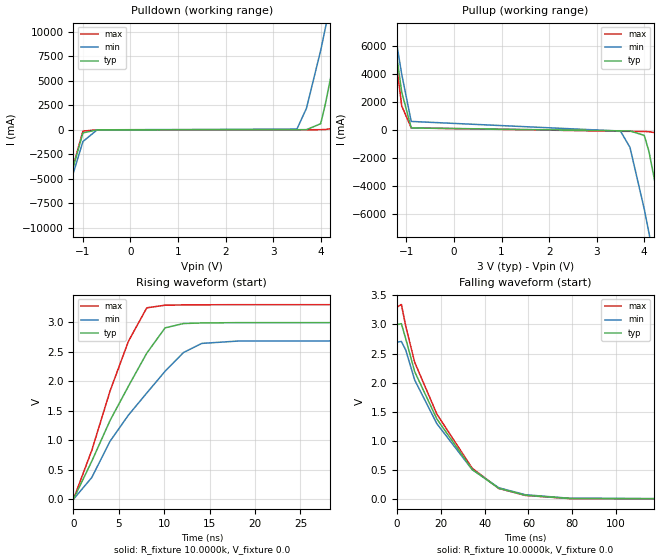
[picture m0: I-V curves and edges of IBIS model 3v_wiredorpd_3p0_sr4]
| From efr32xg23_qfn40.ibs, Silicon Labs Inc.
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|   Model 3v_wiredorpd_3p0_sr4
[Model]  3v_wiredorpd_3p0_sr4
Model_type Output
Polarity   Non-Inverting
Enable   Active-Low
C_comp   1.6300pF   1.4000pF   2.7000pF
[Temperature Range]   25.0000   0.1250k   -40.0000
[Pullup Reference]   3.0000V   2.7000V   3.3000V
[Pulldown Reference]   0.0V   0.0V   0.0V
[POWER Clamp Reference]   3.0000V   2.7000V   3.3000V
[GND Clamp Reference]   0.0V   0.0V   0.0V
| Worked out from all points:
|   slope of the pulldown table from 0 to 0.45 V, typ, clamps not added: 44.2 kohm
|   slope of the pullup table from 0 to 0.45 V, typ, clamps not added: 16.9 ohm
|   rising waveform, R_fixture 10.0000k, V_fixture 0.0: 20-80 % time 5.93ns typ, 7.46ns min, 4.36ns max; typ from 0 V to 3 V
|   falling waveform, R_fixture 10.0000k, V_fixture 0.0: 20-80 % time 26ns typ, 26.5ns min, 25.9ns max; typ from 3 V to 0.001 V
[Pulldown]
|Voltage   I(typ)   I(min)   I(max)
-3V       -32.58A    -30.59A    -34.3A
-1.6V     -10.63A    -10.8A     -10.59A
-1V       -326.2mA   -1.208A    -136.7mA
-700mV    -7.469mA   -9.021mA   -8.251mA
3.5V      668.1uA    66.94mA    91.83uA
3.7V      6.233mA    2.175A     116.2uA
4V        614.2mA    8.096A     6.599mA
4.1V      2.659A     10.42A     23.14mA
4.3V      7.504A     15.17A     173.2mA
4.4V      10.17A     17.48A     1.662A
4.7V      18.27A     24.04A     10.12A
6V        48.87A     49.4A      46.09A
[Pullup]
|Voltage   I(typ)   I(min)   I(max)
-3V       48.87A     43.6A      53.88A
-1.3V     7.53A      8.107A     7.175A
-1.1V     2.691A     3.958A     1.702A
-900mV    131.1mA    593mA      129.1mA
3.5V      -77.88mA   -95.53mA   -111.5mA
3.7V      -84.81mA   -1.257A    -111.9mA
4V        -403.8mA   -5.659A    -120.5mA
4.1V      -1.56A     -7.378A    -141.1mA
4.3V      -5.051A    -10.85A    -249.3mA
4.4V      -6.924A    -12.54A    -949.9mA
4.8V      -14.32A    -18.64A    -8.699A
6V        -32.66A    -34.42A    -29.76A
[Ramp]
| variable   typ   min   max
dV/dt_r  1.7973/5.9250n   1.6165/7.4590n   1.9777/4.3592n
dV/dt_f  0.3321/25.2938n   0.2660/26.8420n   0.4115/24.0269n
R_load = 10.0000k
[Rising Waveform]
R_fixture= 10.0000k
V_fixture= 0.0
V_fixture_min= 0.0
V_fixture_max= 0.0
|time   V(typ)   V(min)   V(max)
0s        8.184uV    73.48uV    10.86uV
2.02ns    643.8mV    368.1mV    826.5mV
4.04ns    1.335V     983.7mV    1.834V
6.061ns   1.914V     1.425V     2.674V
8.081ns   2.473V     1.799V     3.24V
10.1ns    2.901V     2.167V     3.284V
12.12ns   2.974V     2.483V     3.289V
14.14ns   2.984V     2.638V     3.291V
18.18ns   2.989V     2.678V     3.293V
200ns     2.995V     2.694V     3.296V
[Falling Waveform]
R_fixture= 10.0000k
V_fixture= 0.0
V_fixture_min= 0.0
V_fixture_max= 0.0
|time   V(typ)   V(min)   V(max)
0s        2.995V     2.694V     3.296V
2.02ns    3.012V     2.707V     3.34V
4.04ns    2.747V     2.556V     2.963V
8.081ns   2.189V     2.046V     2.35V
18.18ns   1.38V      1.298V     1.463V
34.34ns   513.5mV    509.2mV    532.7mV
46.46ns   189.6mV    198.8mV    187.1mV
58.59ns   71.51mV    79.29mV    67.07mV
78.79ns   15.47mV    18.87mV    13.31mV
200ns     709.1uV    979.6uV    561.7uV
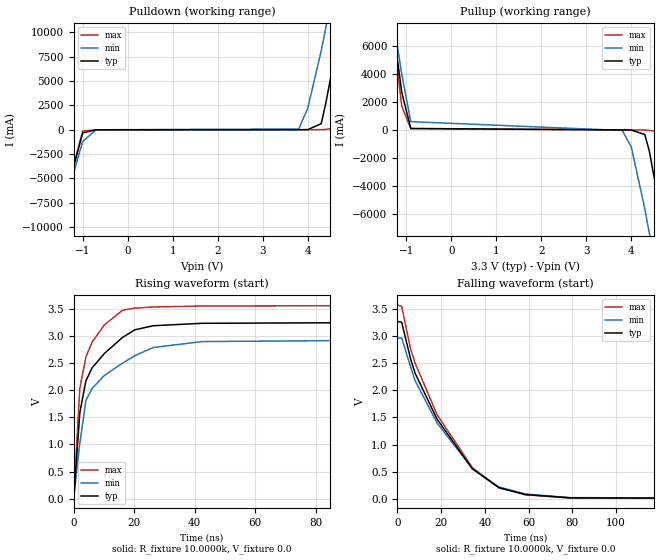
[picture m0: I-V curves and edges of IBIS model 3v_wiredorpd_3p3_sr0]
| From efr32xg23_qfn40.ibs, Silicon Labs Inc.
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|   Model 3v_wiredorpd_3p3_sr0
[Model]  3v_wiredorpd_3p3_sr0
Model_type Output
Polarity   Non-Inverting
Enable   Active-Low
C_comp   1.6300pF   1.4000pF   2.7000pF
[Temperature Range]   25.0000   0.1250k   -40.0000
[Pullup Reference]   3.3000V   3.0000V   3.6000V
[Pulldown Reference]   0.0V   0.0V   0.0V
[POWER Clamp Reference]   3.3000V   3.0000V   3.6000V
[GND Clamp Reference]   0.0V   0.0V   0.0V
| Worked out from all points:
|   slope of the pulldown table from 0 to 0.495 V, typ, clamps not added: 44.1 kohm
|   slope of the pullup table from 0 to 0.495 V, typ, clamps not added: 103 ohm
|   rising waveform, R_fixture 10.0000k, V_fixture 0.0: 20-80 % time 8.22ns typ, 11.4ns min, 5.16ns max; typ from 0 V to 3.27 V
|   falling waveform, R_fixture 10.0000k, V_fixture 0.0: 20-80 % time 26.4ns typ, 26.9ns min, 26.3ns max; typ from 3.27 V to 0.001 V
[Pulldown]
|Voltage   I(typ)   I(min)   I(max)
-3.3V     -36.82A    -34.37A    -38.92A
-1.6V     -10.63A    -10.8A     -10.59A
-1V       -326.3mA   -1.208A    -136.6mA
-700mV    -7.485mA   -9.091mA   -8.244mA
3.8V      676.6uA    67.33mA    99.73uA
4V        6.277mA    2.175A     124.1uA
4.3V      614.5mA    8.098A     6.624mA
4.4V      2.66A      10.42A     23.18mA
4.6V      7.505A     15.17A     173.3mA
4.7V      10.17A     17.48A     1.663A
5V        18.27A     24.04A     10.12A
6.6V      55.71A     55.21A     53.88A
[Pullup]
|Voltage   I(typ)   I(min)   I(max)
-3.3V     55.71A     49.41A     61.66A
-1.3V     7.509A     8.099A     7.144A
-1.1V     2.665A     3.945A     1.669A
-900mV    88.8mA     574.5mA    74.57mA
3.8V      -14.96mA   -56.37mA   -19.92mA
4V        -21.75mA   -1.218A    -20.01mA
4.3V      -340.6mA   -5.62A     -28.27mA
4.4V      -1.497A    -7.339A    -48.76mA
4.6V      -4.988A    -10.81A    -156.7mA
4.7V      -6.861A    -12.5A     -857.2mA
5.1V      -14.26A    -18.6A     -8.605A
6.6V      -36.84A    -38.17A    -34.32A
[Ramp]
| variable   typ   min   max
dV/dt_r  1.9613/8.2170n   1.7760/11.3666n   2.1440/5.1570n
dV/dt_f  0.3658/25.1923n   0.2964/26.6646n   0.4490/23.9678n
R_load = 10.0000k
[Rising Waveform]
R_fixture= 10.0000k
V_fixture= 0.0
V_fixture_min= 0.0
V_fixture_max= 0.0
|time   V(typ)   V(min)   V(max)
0s        10.71uV    77.29uV    19.13uV
2.02ns    1.585V     1.018V     2.032V
4.04ns    2.173V     1.809V     2.616V
6.061ns   2.411V     2.031V     2.884V
10.1ns    2.675V     2.27V      3.202V
16.16ns   2.974V     2.5V       3.475V
20.2ns    3.114V     2.636V     3.514V
26.26ns   3.189V     2.787V     3.535V
42.42ns   3.234V     2.897V     3.553V
200ns     3.269V     2.96V      3.573V
[Falling Waveform]
R_fixture= 10.0000k
V_fixture= 0.0
V_fixture_min= 0.0
V_fixture_max= 0.0
|time   V(typ)   V(min)   V(max)
0s        3.269V     2.962V     3.574V
2.02ns    3.255V     2.964V     3.549V
6.061ns   2.582V     2.435V     2.765V
8.081ns   2.32V      2.182V     2.508V
18.18ns   1.468V     1.398V     1.551V
34.34ns   550.8mV    552.6mV    572.6mV
46.46ns   203.8mV    216.6mV    201.3mV
58.59ns   76.97mV    86.65mV    72.19mV
78.79ns   16.58mV    20.57mV    14.26mV
200ns     704.9uV    972uV      564.6uV
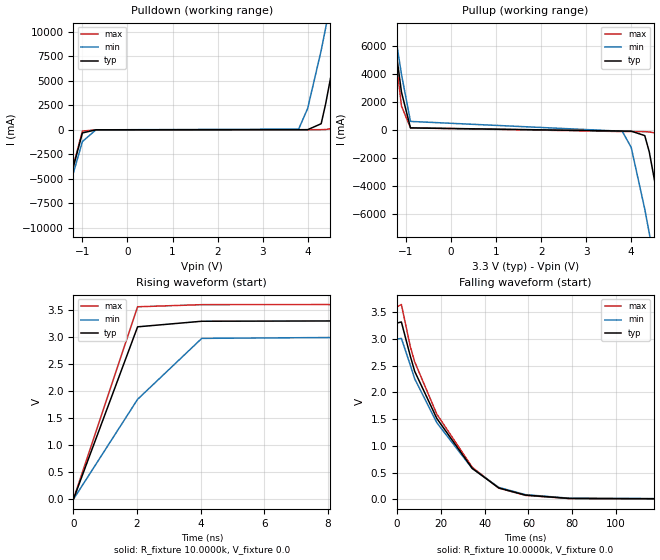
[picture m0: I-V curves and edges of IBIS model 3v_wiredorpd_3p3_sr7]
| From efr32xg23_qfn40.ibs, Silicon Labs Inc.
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|   Model 3v_wiredorpd_3p3_sr7
[Model]  3v_wiredorpd_3p3_sr7
Model_type Output
Polarity   Non-Inverting
Enable   Active-Low
C_comp   1.6300pF   1.4000pF   2.7000pF
[Temperature Range]   25.0000   0.1250k   -40.0000
[Pullup Reference]   3.3000V   3.0000V   3.6000V
[Pulldown Reference]   0.0V   0.0V   0.0V
[POWER Clamp Reference]   3.3000V   3.0000V   3.6000V
[GND Clamp Reference]   0.0V   0.0V   0.0V
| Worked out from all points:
|   slope of the pulldown table from 0 to 0.495 V, typ, clamps not added: 44.1 kohm
|   slope of the pullup table from 0 to 0.495 V, typ, clamps not added: 15.9 ohm
|   rising waveform, R_fixture 10.0000k, V_fixture 0.0: 20-80 % time 1.25ns typ, 2.35ns min, 1.23ns max; typ from 0 V to 3.29 V
|   falling waveform, R_fixture 10.0000k, V_fixture 0.0: 20-80 % time 26.4ns typ, 26.9ns min, 26.3ns max; typ from 3.29 V to 0.001 V
[Pulldown]
|Voltage   I(typ)   I(min)   I(max)
-3.3V     -36.82A    -34.37A    -38.92A
-1.6V     -10.63A    -10.8A     -10.59A
-1V       -326.3mA   -1.208A    -136.6mA
-700mV    -7.485mA   -9.091mA   -8.244mA
3.8V      676.6uA    67.33mA    99.73uA
4V        6.277mA    2.175A     124.1uA
4.3V      614.5mA    8.098A     6.624mA
4.4V      2.66A      10.42A     23.18mA
4.6V      7.505A     15.17A     173.3mA
4.7V      10.17A     17.48A     1.663A
5V        18.27A     24.04A     10.12A
6.6V      55.71A     55.21A     53.88A
[Pullup]
|Voltage   I(typ)   I(min)   I(max)
-3.3V     55.71A     49.41A     61.67A
-1.3V     7.532A     8.11A      7.177A
-1.1V     2.692A     3.96A      1.703A
-900mV    133.8mA    595.4mA    130.8mA
3.8V      -92.75mA   -107.2mA   -128.7mA
4V        -99.72mA   -1.269A    -129.1mA
4.3V      -418.8mA   -5.671A    -137.7mA
4.4V      -1.575A    -7.39A     -158.3mA
4.6V      -5.066A    -10.86A    -266.6mA
4.7V      -6.939A    -12.55A    -967.1mA
5.1V      -14.34A    -18.65A    -8.716A
6.6V      -36.92A    -38.22A    -34.43A
[Ramp]
| variable   typ   min   max
dV/dt_r  1.9771/1.2546n   1.7964/2.3509n   2.1575/1.2263n
dV/dt_f  0.3658/25.1931n   0.2964/26.6553n   0.4490/23.9544n
R_load = 10.0000k
[Rising Waveform]
R_fixture= 10.0000k
V_fixture= 0.0
V_fixture_min= 0.0
V_fixture_max= 0.0
|time   V(typ)   V(min)   V(max)
0s        10.71uV    77.29uV    19.13uV
2.02ns    3.184V     1.846V     3.554V
4.04ns    3.287V     2.971V     3.593V
10.1ns    3.295V     2.994V     3.596V
200ns     3.295V     2.994V     3.596V
[Falling Waveform]
R_fixture= 10.0000k
V_fixture= 0.0
V_fixture_min= 0.0
V_fixture_max= 0.0
|time   V(typ)   V(min)   V(max)
0s        3.295V     2.994V     3.596V
2.02ns    3.314V     3.008V     3.641V
6.061ns   2.681V     2.512V     2.859V
8.081ns   2.393V     2.253V     2.57V
18.18ns   1.512V     1.433V     1.592V
34.34ns   579.9mV    575.9mV    600mV
46.46ns   213.1mV    223.4mV    209.9mV
58.59ns   79.88mV    88.37mV    74.9mV
78.79ns   17mV       20.64mV    14.66mV
200ns     707.7uV    975uV      566.3uV
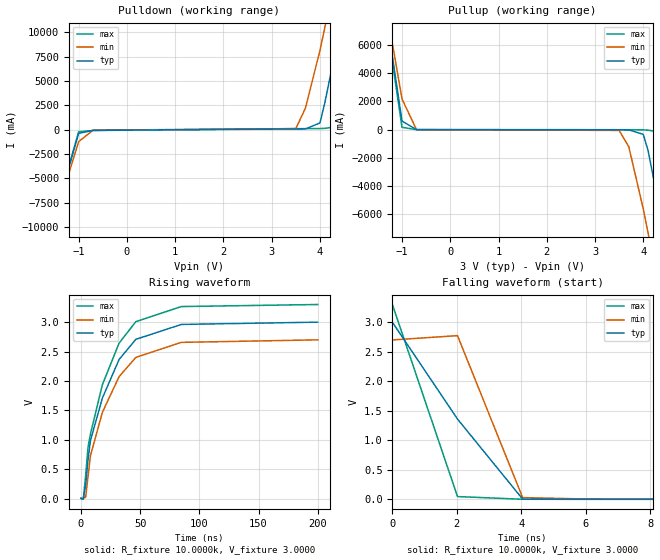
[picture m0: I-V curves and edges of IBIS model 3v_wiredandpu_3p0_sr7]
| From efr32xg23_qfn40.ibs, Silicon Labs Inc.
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|   Model 3v_wiredandpu_3p0_sr7
[Model]  3v_wiredandpu_3p0_sr7
Model_type Output
Polarity   Inverting
Enable   Active-Low
C_comp   1.6300pF   1.4000pF   2.7000pF
[Temperature Range]   25.0000   0.1250k   -40.0000
[Pullup Reference]   3.0000V   2.7000V   3.3000V
[Pulldown Reference]   0.0V   0.0V   0.0V
[POWER Clamp Reference]   3.0000V   2.7000V   3.3000V
[GND Clamp Reference]   0.0V   0.0V   0.0V
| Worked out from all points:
|   slope of the pulldown table from 0 to 0.45 V, typ, clamps not added: 13.2 ohm
|   slope of the pullup table from 0 to 0.45 V, typ, clamps not added: 44.4 kohm
|   rising waveform, R_fixture 10.0000k, V_fixture 3.0000: 20-80 % time 27.6ns typ, 28.1ns min, 27ns max; typ from 0.003 V to 3 V
|   falling waveform, R_fixture 10.0000k, V_fixture 3.0000: 20-80 % time 2.41ns typ, 1.19ns min, 1.23ns max; typ from 3 V to 0.003 V
[Pulldown]
|Voltage   I(typ)   I(min)   I(max)
-3V       -32.58A    -30.59A    -34.31A
-1.6V     -10.64A    -10.81A    -10.62A
-1V       -369.5mA   -1.223A    -213mA
-700mV    -60.92mA   -44.3mA    -77.77mA
3.5V      79.82mA    115.9mA    114.1mA
3.7V      85.6mA     2.224A     114.4mA
4V        694.1mA    8.145A     121.6mA
4.1V      2.74A      10.47A     138.5mA
4.3V      7.585A     15.22A     289.6mA
4.4V      10.25A     17.53A     1.779A
4.7V      18.35A     24.09A     10.24A
6V        48.97A     49.46A     46.24A
[Pullup]
|Voltage   I(typ)   I(min)   I(max)
-3V       48.87A     43.59A     53.88A
-1.3V     7.504A     8.096A     7.139A
-1V       614.1mA    2.175A     173.2mA
-700mV    6.165mA    10.06mA    6.512mA
3.5V      -793uA     -46.9mA    -91.34uA
3.7V      -7.536mA   -1.208A    -137.9uA
4V        -326.3mA   -5.611A    -8.337mA
4.1V      -1.482A    -7.329A    -28.82mA
4.3V      -4.973A    -10.8A     -136.8mA
4.4V      -6.846A    -12.49A    -837.2mA
4.8V      -14.25A    -18.59A    -8.585A
6V        -32.58A    -34.37A    -29.65A
[Ramp]
| variable   typ   min   max
dV/dt_r  0.3310/16.3058n   0.2657/17.1336n   0.4098/15.5411n
dV/dt_f  1.7980/2.4127n   1.6171/1.1917n   1.9783/1.2295n
R_load = 10.0000k
[Rising Waveform]
R_fixture= 10.0000k
V_fixture= 3.0000
V_fixture_min= 2.7000
V_fixture_max= 3.3000
|time   V(typ)   V(min)   V(max)
0s        3.402mV    4.707mV    2.76mV
2.02ns    -8.385mV   913.1uV    -12.93mV
4.04ns    224.8mV    23.69mV    393.8mV
6.061ns   663.7mV    376.7mV    875.2mV
8.081ns   985.6mV    729mV      1.099V
18.18ns   1.71V      1.468V     1.937V
32.32ns   2.367V     2.075V     2.645V
46.46ns   2.708V     2.401V     3.009V
84.85ns   2.961V     2.656V     3.265V
200ns     3V         2.699V     3.3V
[Falling Waveform]
R_fixture= 10.0000k
V_fixture= 3.0000
V_fixture_min= 2.7000
V_fixture_max= 3.3000
|time   V(typ)   V(min)   V(max)
0s        3V         2.7V       3.3V
2.02ns    1.361V     2.773V     49.4mV
4.04ns    6.705mV    31.93mV    3.775mV
6.061ns   3.995mV    7.735mV    2.926mV
10.1ns    3.445mV    4.945mV    2.777mV
200ns     3.403mV    4.709mV    2.761mV
